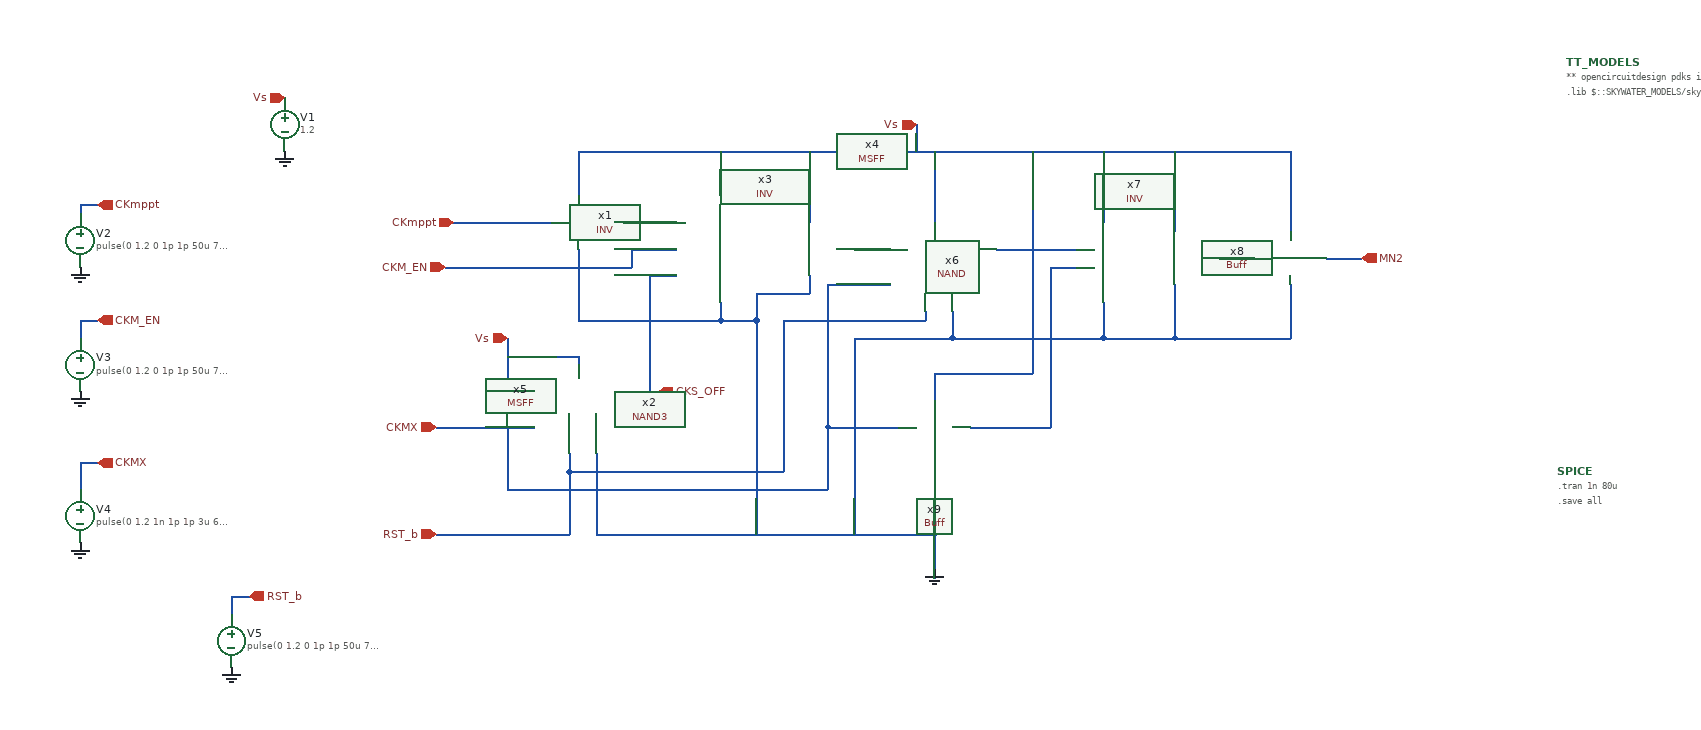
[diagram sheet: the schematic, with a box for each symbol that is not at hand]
v {xschem version=3.0.0 file_version=1.2 }
G {}
K {}
V {}
S {}
E {}
N -380 -170 -320 -170 {
lab=#net1}
N -510 -170 -460 -170 {
lab=CKmppt}
N -340 -140 -320 -140 {
lab=CKM_EN}
N -370 -140 -340 -140 {
lab=CKM_EN}
N -370 -140 -370 -120 {
lab=CKM_EN}
N -510 -120 -370 -120 {
lab=CKM_EN}
N -340 -110 -320 -110 {
lab=CKS_OFF}
N 40 -140 130 -140 {
lab=#net2}
N 290 -130 330 -130 {
lab=#net3}
N 410 -130 450 -130 {
lab=MN2}
N 10 60 100 60 {
lab=#net4}
N 100 -120 100 60 {
lab=#net4}
N 100 -120 130 -120 {
lab=#net4}
N -510 20 -480 20 {
lab=Vs}
N -510 -40 -510 20 {
lab=Vs}
N -510 -20 -450 -20 {
lab=Vs}
N -40 -70 -40 -60 {
lab=RST_b}
N -540 60 -480 60 {
lab=CKMX}
N -510 60 -510 110 {
lab=CKMX}
N -510 110 -510 130 {
lab=CKMX}
N -510 130 -150 130 {
lab=CKMX}
N -150 70 -150 130 {
lab=CKMX}
N -150 60 -150 70 {
lab=CKMX}
N -150 60 -70 60 {
lab=CKMX}
N -200 -20 -200 100 {
lab=RST_b}
N -440 110 -200 110 {
lab=RST_b}
N -440 90 -440 100 {
lab=RST_b}
N -200 100 -200 110 {
lab=RST_b}
N -440 100 -440 110 {
lab=RST_b}
N -440 110 -440 180 {
lab=RST_b}
N -540 180 -440 180 {
lab=RST_b}
N -590 180 -540 180 {
lab=RST_b}
N -590 60 -540 60 {
lab=CKMX}
N -580 -120 -510 -120 {
lab=CKM_EN}
N -570 -170 -510 -170 {
lab=CKmppt}
N -360 20 -340 20 {
lab=CKS_OFF}
N -120 -140 -80 -140 {
lab=#net5}
N -150 -70 -150 60 {
lab=CKMX}
N -130 -100 -80 -100 {
lab=CKMX}
N -410 90 -410 180 {
lab=GND}
N -410 180 -30 180 {
lab=GND}
N -30 90 -30 180 {
lab=GND}
N -10 -70 -10 -50 {
lab=GND}
N -150 -100 -150 -70 {
lab=CKMX}
N -150 -100 -130 -100 {
lab=CKMX}
N -200 -60 -200 -20 {
lab=RST_b}
N -200 -60 -40 -60 {
lab=RST_b}
N -10 -50 -10 -40 {
lab=GND}
N -120 -40 -10 -40 {
lab=GND}
N -120 -40 -120 180 {
lab=GND}
N -30 180 -30 230 {
lab=GND}
N -430 -140 -430 -70 {
lab=GND}
N -430 -70 -430 -60 {
lab=GND}
N -430 -60 -270 -60 {
lab=GND}
N -270 -80 -270 -60 {
lab=GND}
N -230 -60 -230 180 {
lab=GND}
N -170 -110 -170 -90 {
lab=GND}
N -230 -90 -170 -90 {
lab=GND}
N -230 -90 -230 -60 {
lab=GND}
N -270 -60 -230 -60 {
lab=GND}
N 160 -80 160 -40 {
lab=GND}
N -10 -40 160 -40 {
lab=GND}
N 370 -100 370 -80 {
lab=GND}
N 240 -100 240 -40 {
lab=GND}
N 370 -80 370 -40 {
lab=GND}
N 240 -40 370 -40 {
lab=GND}
N 160 -40 240 -40 {
lab=GND}
N -430 -250 360 -250 {
lab=Vs}
N 360 -250 370 -250 {
lab=Vs}
N 370 -250 370 -160 {
lab=Vs}
N 240 -250 240 -160 {
lab=Vs}
N 160 -250 160 -170 {
lab=Vs}
N -30 -250 -30 -170 {
lab=Vs}
N -170 -250 -170 -170 {
lab=Vs}
N -270 -250 -270 -200 {
lab=Vs}
N -430 -250 -430 -200 {
lab=Vs}
N -30 0 -30 30 {
lab=Vs}
N -30 0 80 0 {
lab=Vs}
N 80 -250 80 0 {
lab=Vs}
N -50 -280 -50 -250 {
lab=Vs}
N -350 -110 -340 -110 {
lab=CKS_OFF}
N -350 -110 -350 20 {
lab=CKS_OFF}
N -450 -20 -430 -20 {
lab=Vs}
N -430 -20 -430 -10 {
lab=Vs}
N -990 -190 -970 -190 {
lab=CKmppt}
N -990 -190 -990 -180 {
lab=CKmppt}
N -990 -60 -970 -60 {
lab=CKM_EN}
N -990 -60 -990 -40 {
lab=CKM_EN}
N -990 100 -970 100 {
lab=CKMX}
N -990 100 -990 130 {
lab=CKMX}
N -820 250 -800 250 {
lab=RST_b}
N -820 250 -820 270 {
lab=RST_b}
C {devices/ipin.sym} -570 -170 0 0 {name=p1 lab=CKmppt}
C {devices/ipin.sym} -580 -120 0 0 {name=p2 lab=CKM_EN}
C {devices/ipin.sym} -590 60 0 0 {name=p3 lab=CKMX}
C {devices/ipin.sym} -590 180 0 0 {name=p4 lab=RST_b}
C {devices/iopin.sym} -50 -280 3 0 {name=p5 lab=Vs}
C {devices/gnd.sym} -30 220 0 0 {name=l1 lab=GND}
C {devices/iopin.sym} -510 -40 3 0 {name=p6 lab=Vs}
C {devices/opin.sym} 450 -130 0 0 {name=p7 lab=MN2}
C {devices/opin.sym} -340 20 0 0 {name=p8 lab=CKS_OFF}
C {CCC/StdINV & RdnINV/INV.sym} -480 -170 0 0 {name=x1}
C {CCC/NAND/NAND3.sym} -360 -100 0 0 {name=x2}
C {CCC/StdINV & RdnINV/INV.sym} -220 -140 0 0 {name=x3}
C {CCC/FlipFlops/MSFF.sym} -110 -100 0 0 {name=x4}
C {CCC/FlipFlops/MSFF.sym} -510 60 0 0 {name=x5}
C {CCC/NAND/NAND.sym} -10 -80 0 0 {name=x6}
C {CCC/StdINV & RdnINV/INV.sym} 190 -130 0 0 {name=x7}
C {CCC/Buffer/Buff.sym} 300 -130 0 0 {name=x8}
C {CCC/Buffer/Buff.sym} -100 60 0 0 {name=x9}
C {devices/code.sym} 680 -350 0 0 {name=TT_MODELS
only_toplevel=true
format="tcleval( @value )"
value="
** opencircuitdesign pdks install
.lib $::SKYWATER_MODELS/sky130.lib.spice tt

"
spice_ignore=false}
C {devices/vsource.sym} -760 -280 0 0 {name=V1 value=1.2}
C {devices/vsource.sym} -990 -150 0 0 {name=V2 value="pulse(0 1.2 0 1p 1p 50u 70u)"}
C {devices/vsource.sym} -990 -10 0 0 {name=V3 value="pulse(0 1.2 0 1p 1p 50u 70u)"}
C {devices/vsource.sym} -990 160 0 0 {name=V4 value="pulse(0 1.2 1n 1p 1p 3u 6u)"}
C {devices/vsource.sym} -820 300 0 0 {name=V5 value="pulse(0 1.2 0 1p 1p 50u 70u)"}
C {devices/gnd.sym} -760 -250 0 0 {name=l2 lab=GND}
C {devices/gnd.sym} -990 -120 0 0 {name=l3 lab=GND}
C {devices/gnd.sym} -990 20 0 0 {name=l4 lab=GND}
C {devices/gnd.sym} -990 190 0 0 {name=l5 lab=GND}
C {devices/gnd.sym} -820 330 0 0 {name=l6 lab=GND}
C {devices/iopin.sym} -760 -310 3 0 {name=p9 lab=Vs}
C {devices/opin.sym} -970 -190 0 0 {name=p10 lab=CKmppt}
C {devices/opin.sym} -970 -60 0 0 {name=p11 lab=CKM_EN}
C {devices/opin.sym} -970 100 0 0 {name=p12 lab=CKMX}
C {devices/opin.sym} -800 250 0 0 {name=p13 lab=RST_b}
C {devices/code_shown.sym} 670 110 0 0 {name=SPICE only_toplevel=false value=".tran 1n 80u
.save all"}
